One B-rep face of a CAD part: STEP entity #37494.
In plain terms, the planar face has unit normal (0, 0, 1).
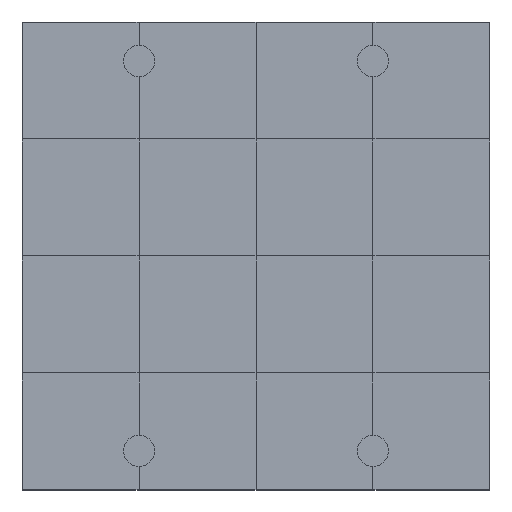
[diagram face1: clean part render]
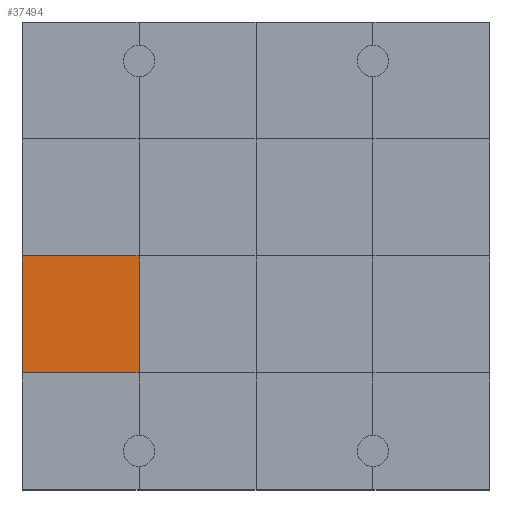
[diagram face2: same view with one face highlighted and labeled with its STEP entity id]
Its self-contained STEP definition (entity closure, numbers rounded to 3 decimals):
#37044 = VERTEX_POINT('',#37045);
#37045 = CARTESIAN_POINT('',(0.,3.,1.2));
#37059 = PLANE('',#37060);
#37060 = AXIS2_PLACEMENT_3D('',#37061,#37062,#37063);
#37061 = CARTESIAN_POINT('',(0.,3.,0.));
#37062 = DIRECTION('',(1.,0.,-0.));
#37063 = DIRECTION('',(0.,0.,1.));
#37085 = PLANE('',#37086);
#37086 = AXIS2_PLACEMENT_3D('',#37087,#37088,#37089);
#37087 = CARTESIAN_POINT('',(0.,0.,1.2));
#37088 = DIRECTION('',(0.,0.,1.));
#37089 = DIRECTION('',(1.,0.,-0.));
#37236 = VERTEX_POINT('',#37237);
#37237 = CARTESIAN_POINT('',(3.,3.,1.2));
#37258 = EDGE_CURVE('',#37044,#37236,#37259,.T.);
#37259 = SURFACE_CURVE('',#37260,(#37264,#37271),.PCURVE_S1.);
#37260 = LINE('',#37261,#37262);
#37261 = CARTESIAN_POINT('',(0.,3.,1.2));
#37262 = VECTOR('',#37263,1.);
#37263 = DIRECTION('',(1.,0.,-0.));
#37264 = PCURVE('',#37085,#37265);
#37265 = DEFINITIONAL_REPRESENTATION('',(#37266),#37270);
#37266 = LINE('',#37267,#37268);
#37267 = CARTESIAN_POINT('',(0.,3.));
#37268 = VECTOR('',#37269,1.);
#37269 = DIRECTION('',(1.,0.));
#37270 = ( GEOMETRIC_REPRESENTATION_CONTEXT(2) 
PARAMETRIC_REPRESENTATION_CONTEXT() REPRESENTATION_CONTEXT('2D SPACE',''
  ) );
#37271 = PCURVE('',#37272,#37277);
#37272 = PLANE('',#37273);
#37273 = AXIS2_PLACEMENT_3D('',#37274,#37275,#37276);
#37274 = CARTESIAN_POINT('',(0.,3.,1.2));
#37275 = DIRECTION('',(0.,0.,1.));
#37276 = DIRECTION('',(1.,0.,-0.));
#37277 = DEFINITIONAL_REPRESENTATION('',(#37278),#37282);
#37278 = LINE('',#37279,#37280);
#37279 = CARTESIAN_POINT('',(0.,0.));
#37280 = VECTOR('',#37281,1.);
#37281 = DIRECTION('',(1.,0.));
#37282 = ( GEOMETRIC_REPRESENTATION_CONTEXT(2) 
PARAMETRIC_REPRESENTATION_CONTEXT() REPRESENTATION_CONTEXT('2D SPACE',''
  ) );
#37317 = VERTEX_POINT('',#37318);
#37318 = CARTESIAN_POINT('',(0.,6.,1.2));
#37344 = EDGE_CURVE('',#37044,#37317,#37345,.T.);
#37345 = SURFACE_CURVE('',#37346,(#37350,#37357),.PCURVE_S1.);
#37346 = LINE('',#37347,#37348);
#37347 = CARTESIAN_POINT('',(0.,3.,1.2));
#37348 = VECTOR('',#37349,1.);
#37349 = DIRECTION('',(-0.,1.,0.));
#37350 = PCURVE('',#37059,#37351);
#37351 = DEFINITIONAL_REPRESENTATION('',(#37352),#37356);
#37352 = LINE('',#37353,#37354);
#37353 = CARTESIAN_POINT('',(1.2,0.));
#37354 = VECTOR('',#37355,1.);
#37355 = DIRECTION('',(0.,-1.));
#37356 = ( GEOMETRIC_REPRESENTATION_CONTEXT(2) 
PARAMETRIC_REPRESENTATION_CONTEXT() REPRESENTATION_CONTEXT('2D SPACE',''
  ) );
#37357 = PCURVE('',#37272,#37358);
#37358 = DEFINITIONAL_REPRESENTATION('',(#37359),#37363);
#37359 = LINE('',#37360,#37361);
#37360 = CARTESIAN_POINT('',(0.,0.));
#37361 = VECTOR('',#37362,1.);
#37362 = DIRECTION('',(0.,1.));
#37363 = ( GEOMETRIC_REPRESENTATION_CONTEXT(2) 
PARAMETRIC_REPRESENTATION_CONTEXT() REPRESENTATION_CONTEXT('2D SPACE',''
  ) );
#37494 = ADVANCED_FACE('',(#37495),#37272,.T.);
#37495 = FACE_BOUND('',#37496,.T.);
#37496 = EDGE_LOOP('',(#37497,#37498,#37499,#37527));
#37497 = ORIENTED_EDGE('',*,*,#37344,.F.);
#37498 = ORIENTED_EDGE('',*,*,#37258,.T.);
#37499 = ORIENTED_EDGE('',*,*,#37500,.T.);
#37500 = EDGE_CURVE('',#37236,#37501,#37503,.T.);
#37501 = VERTEX_POINT('',#37502);
#37502 = CARTESIAN_POINT('',(3.,6.,1.2));
#37503 = SURFACE_CURVE('',#37504,(#37508,#37515),.PCURVE_S1.);
#37504 = LINE('',#37505,#37506);
#37505 = CARTESIAN_POINT('',(3.,3.,1.2));
#37506 = VECTOR('',#37507,1.);
#37507 = DIRECTION('',(-0.,1.,0.));
#37508 = PCURVE('',#37272,#37509);
#37509 = DEFINITIONAL_REPRESENTATION('',(#37510),#37514);
#37510 = LINE('',#37511,#37512);
#37511 = CARTESIAN_POINT('',(3.,0.));
#37512 = VECTOR('',#37513,1.);
#37513 = DIRECTION('',(0.,1.));
#37514 = ( GEOMETRIC_REPRESENTATION_CONTEXT(2) 
PARAMETRIC_REPRESENTATION_CONTEXT() REPRESENTATION_CONTEXT('2D SPACE',''
  ) );
#37515 = PCURVE('',#37516,#37521);
#37516 = PLANE('',#37517);
#37517 = AXIS2_PLACEMENT_3D('',#37518,#37519,#37520);
#37518 = CARTESIAN_POINT('',(3.,3.,1.2));
#37519 = DIRECTION('',(0.,0.,1.));
#37520 = DIRECTION('',(1.,0.,-0.));
#37521 = DEFINITIONAL_REPRESENTATION('',(#37522),#37526);
#37522 = LINE('',#37523,#37524);
#37523 = CARTESIAN_POINT('',(0.,0.));
#37524 = VECTOR('',#37525,1.);
#37525 = DIRECTION('',(0.,1.));
#37526 = ( GEOMETRIC_REPRESENTATION_CONTEXT(2) 
PARAMETRIC_REPRESENTATION_CONTEXT() REPRESENTATION_CONTEXT('2D SPACE',''
  ) );
#37527 = ORIENTED_EDGE('',*,*,#37528,.F.);
#37528 = EDGE_CURVE('',#37317,#37501,#37529,.T.);
#37529 = SURFACE_CURVE('',#37530,(#37534,#37541),.PCURVE_S1.);
#37530 = LINE('',#37531,#37532);
#37531 = CARTESIAN_POINT('',(0.,6.,1.2));
#37532 = VECTOR('',#37533,1.);
#37533 = DIRECTION('',(1.,0.,-0.));
#37534 = PCURVE('',#37272,#37535);
#37535 = DEFINITIONAL_REPRESENTATION('',(#37536),#37540);
#37536 = LINE('',#37537,#37538);
#37537 = CARTESIAN_POINT('',(0.,3.));
#37538 = VECTOR('',#37539,1.);
#37539 = DIRECTION('',(1.,0.));
#37540 = ( GEOMETRIC_REPRESENTATION_CONTEXT(2) 
PARAMETRIC_REPRESENTATION_CONTEXT() REPRESENTATION_CONTEXT('2D SPACE',''
  ) );
#37541 = PCURVE('',#37542,#37547);
#37542 = PLANE('',#37543);
#37543 = AXIS2_PLACEMENT_3D('',#37544,#37545,#37546);
#37544 = CARTESIAN_POINT('',(0.,6.,1.2));
#37545 = DIRECTION('',(0.,0.,1.));
#37546 = DIRECTION('',(1.,0.,-0.));
#37547 = DEFINITIONAL_REPRESENTATION('',(#37548),#37552);
#37548 = LINE('',#37549,#37550);
#37549 = CARTESIAN_POINT('',(0.,0.));
#37550 = VECTOR('',#37551,1.);
#37551 = DIRECTION('',(1.,0.));
#37552 = ( GEOMETRIC_REPRESENTATION_CONTEXT(2) 
PARAMETRIC_REPRESENTATION_CONTEXT() REPRESENTATION_CONTEXT('2D SPACE',''
  ) );
